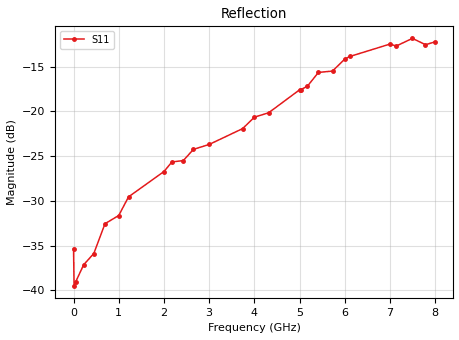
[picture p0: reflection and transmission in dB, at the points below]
!  22/10/2019  12:14:53
! Ref Plane: 0.000 mm
# MHZ S MA R  50
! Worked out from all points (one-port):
!   2001 points, 300 kHz to 8 GHz, reference 50 ohm
!   lowest |S11| = -39.5 dB at 12.3 MHz (marker M1), VSWR 1.02, Z = 51.1 - j0.0415 ohm
!   |S11| at or under -10 dB: start of sweep to end of sweep
!   S11 on the Smith chart (normalised r, x): 300 kHz: 1.02, -0.03; 5.024 GHz: 0.79, +0.11; 6.112 GHz: 0.87, +0.36; 7.136 GHz: 1.18, +0.48; 8 GHz: 1.57, +0.28
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0.3  0.01714 -50.8
12.2997  0.01063 -2.2
48.2988  0.01117 3.9
224.2944  0.01391 20.5
448.2888  0.01607 14.7
696.2826  0.02358 10.7
1000.275  0.0262 0.5
1216.27  0.03327 -6.8
2000.25  0.04611 -44.8
2176.246  0.05216 -51.0
2428.239  0.05307 -64.2
2652.234  0.06131 -75.9
3000.225  0.06529 -95.6
3740.206  0.08005 -137.7
4000.2  0.0927 -156.8
4316.192  0.09815 -171.0
5000.175  0.1318 151.5
5024.174  0.132 150.1
5172.171  0.138 140.1
5416.165  0.1648 127.5
5728.157  0.1677 115.0
6000.15  0.1958 101.3
6112.147  0.2023 98.5
7000.125  0.2373 64.1
7136.122  0.2313 56.8
7496.113  0.2553 42.8
7784.105  0.2354 31.4
8000.1  0.2442 20.0
